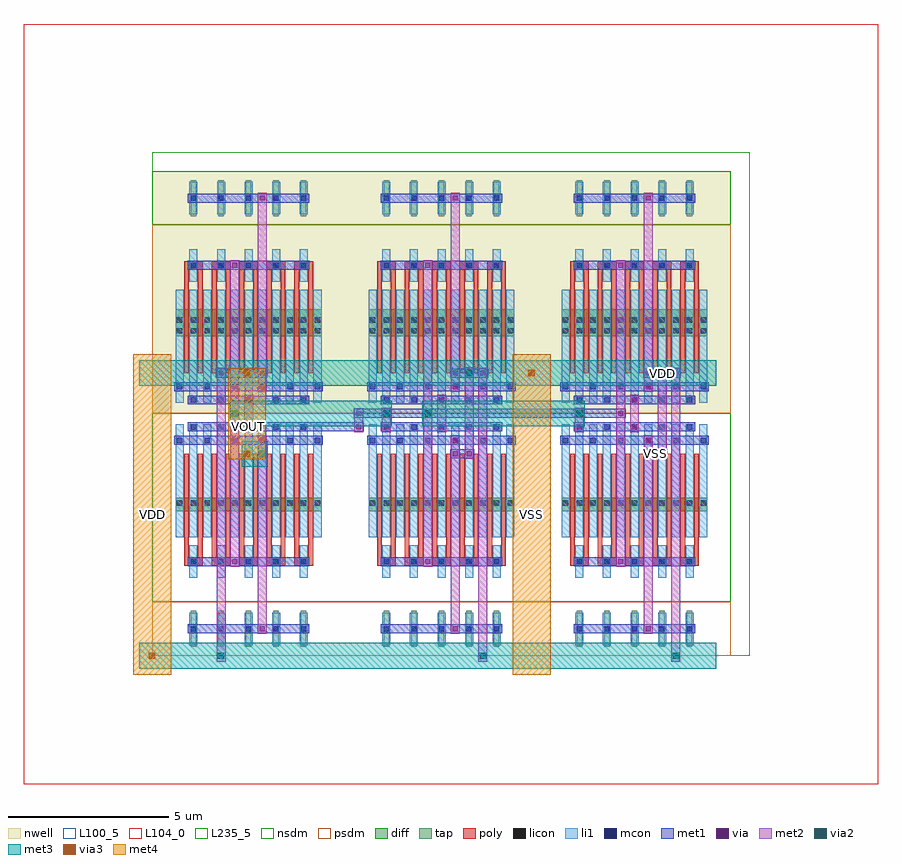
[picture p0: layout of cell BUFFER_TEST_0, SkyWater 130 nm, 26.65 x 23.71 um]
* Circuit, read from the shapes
.subckt BUFFER_TEST_0 VDD VOUT VSS
XM1 VOUT n1 VSS VSS sky130_fd_pr__nfet_01v8 w=0.42 l=0.15 m=10
XM2 n1 n2 VSS VSS sky130_fd_pr__nfet_01v8 w=0.42 l=0.15 m=10
XM3 n2 VOUT VSS VSS sky130_fd_pr__nfet_01v8 w=0.42 l=0.15 m=10
XM4 VOUT n1 VDD VDD sky130_fd_pr__pfet_01v8 w=0.84 l=0.15 m=10
XM5 n1 n2 VDD VDD sky130_fd_pr__pfet_01v8 w=0.84 l=0.15 m=10
XM6 n2 VOUT VDD VDD sky130_fd_pr__pfet_01v8 w=0.84 l=0.15 m=10
.ends

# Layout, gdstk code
import gdstk
lib = gdstk.Library(unit=1e-6, precision=1e-09)
def R(c, l, rs):  # rectangles x0, y0, x1, y1
    for r in rs: c.add(gdstk.rectangle(r[:2], r[2:], *l))
def A(c, l, x, y, w, h, nx, ny, dx, dy):  # array of equal rectangles
    R(c, l, [(x+i*dx, y+j*dy, x+i*dx+w, y+j*dy+h) for i in range(nx) for j in range(ny)])
def P(c, l, *ps):  # polygons
    for p in ps: c.add(gdstk.Polygon(p, *l))
nwell = (64, 20)
diff = (65, 20)
tap = (65, 44)
poly = (66, 20)
licon = (66, 44)
li1 = (67, 20)
mcon = (67, 44)
met1 = (68, 20)
via = (68, 44)
met2 = (69, 20)
via2 = (69, 44)
met3 = (70, 20)
via3 = (70, 44)
met4 = (71, 20)
nsdm = (93, 44)
psdm = (94, 20)
L100_5 = (100, 5)
L104_0 = (104, 0)
L235_5 = (235, 5)

nmos_s_94100000_x5_y1_16 = lib.new_cell('NMOS_S_94100000_X5_Y1_1677907802_1677907802_1677907802')
R(nmos_s_94100000_x5_y1_16, diff, [(0.735,2.625,5.285,3.045)])
A(nmos_s_94100000_x5_y1_16, tap, 1.205, 6.16, 0.17, 1.12, 5, 1, 0.86, 0)
A(nmos_s_94100000_x5_y1_16, poly, 1, 1.26, 0.15, 3.36, 10, 1, 0.43, 0)
A(nmos_s_94100000_x5_y1_16, poly, 1, 4.485, 0.58, 0.27, 5, 1, 0.86, 0)
A(nmos_s_94100000_x5_y1_16, licon, 0.775, 2.705, 0.17, 0.17, 3, 1, 0.43, 0)
A(nmos_s_94100000_x5_y1_16, licon, 1.635, 2.705, 0.17, 0.17, 3, 1, 0.43, 0)
A(nmos_s_94100000_x5_y1_16, licon, 2.495, 2.705, 0.17, 0.17, 3, 1, 0.43, 0)
A(nmos_s_94100000_x5_y1_16, licon, 3.355, 2.705, 0.17, 0.17, 3, 1, 0.43, 0)
A(nmos_s_94100000_x5_y1_16, licon, 4.215, 2.705, 0.17, 0.17, 3, 1, 0.43, 0)
A(nmos_s_94100000_x5_y1_16, licon, 1.205, 4.535, 0.17, 0.17, 5, 2, 0.86, 2.1)
A(nmos_s_94100000_x5_y1_16, li1, 0.735, 0.335, 0.25, 3.53, 11, 1, 0.43, 0)
A(nmos_s_94100000_x5_y1_16, li1, 1.165, 4.115, 0.25, 1.01, 5, 2, 0.86, 2.1)
A(nmos_s_94100000_x5_y1_16, mcon, 1.205, 0.335, 0.17, 0.17, 5, 2, 0.86, 4.2)
A(nmos_s_94100000_x5_y1_16, mcon, 0.775, 0.755, 0.17, 0.17, 6, 1, 0.86, 0)
A(nmos_s_94100000_x5_y1_16, mcon, 1.205, 6.635, 0.17, 0.17, 5, 1, 0.86, 0)
R(nmos_s_94100000_x5_y1_16, met1, [(1.12,0.28,4.9,0.56), (0.69,0.7,5.33,0.98), (1.12,4.48,4.9,4.76), (1.12,6.58,4.9,6.86)])
R(nmos_s_94100000_x5_y1_16, via, [(3.365,0.765,3.515,0.915), (3.365,6.645,3.515,6.795)])
R(nmos_s_94100000_x5_y1_16, met2, [(3.3,0.68,3.58,6.88)])
R(nmos_s_94100000_x5_y1_16, nsdm, [(0,0,6.02,5.88)])
R(nmos_s_94100000_x5_y1_16, psdm, [(0,5.88,6.02,7.56)])
R(nmos_s_94100000_x5_y1_16, L100_5, [(0,0,6.02,7.56)])

pmos_s_16969580_x5_y1_16 = lib.new_cell('PMOS_S_16969580_X5_Y1_1677907803_1677907802_1677907802')
R(pmos_s_16969580_x5_y1_16, nwell, [(0,0,6.02,7.56)])
R(pmos_s_16969580_x5_y1_16, diff, [(0.735,2.415,5.285,3.255)])
A(pmos_s_16969580_x5_y1_16, tap, 1.205, 6.16, 0.17, 1.12, 5, 1, 0.86, 0)
A(pmos_s_16969580_x5_y1_16, poly, 1, 1.26, 0.15, 3.36, 10, 1, 0.43, 0)
A(pmos_s_16969580_x5_y1_16, poly, 1, 4.485, 0.58, 0.27, 5, 1, 0.86, 0)
A(pmos_s_16969580_x5_y1_16, licon, 0.775, 2.495, 0.17, 0.17, 3, 2, 0.43, 0.34)
A(pmos_s_16969580_x5_y1_16, licon, 1.635, 2.495, 0.17, 0.17, 3, 2, 0.43, 0.34)
A(pmos_s_16969580_x5_y1_16, licon, 2.495, 2.495, 0.17, 0.17, 3, 2, 0.43, 0.34)
A(pmos_s_16969580_x5_y1_16, licon, 3.355, 2.495, 0.17, 0.17, 3, 2, 0.43, 0.34)
A(pmos_s_16969580_x5_y1_16, licon, 4.215, 2.495, 0.17, 0.17, 3, 2, 0.43, 0.34)
A(pmos_s_16969580_x5_y1_16, licon, 1.205, 4.535, 0.17, 0.17, 5, 2, 0.86, 2.1)
A(pmos_s_16969580_x5_y1_16, li1, 0.735, 0.335, 0.25, 3.53, 11, 1, 0.43, 0)
A(pmos_s_16969580_x5_y1_16, li1, 1.165, 4.115, 0.25, 1.01, 5, 2, 0.86, 2.1)
A(pmos_s_16969580_x5_y1_16, mcon, 1.205, 0.335, 0.17, 0.17, 5, 2, 0.86, 4.2)
A(pmos_s_16969580_x5_y1_16, mcon, 0.775, 0.755, 0.17, 0.17, 6, 1, 0.86, 0)
A(pmos_s_16969580_x5_y1_16, mcon, 1.205, 6.635, 0.17, 0.17, 5, 1, 0.86, 0)
R(pmos_s_16969580_x5_y1_16, met1, [(1.12,0.28,4.9,0.56), (0.69,0.7,5.33,0.98), (1.12,4.48,4.9,4.76), (1.12,6.58,4.9,6.86)])
R(pmos_s_16969580_x5_y1_16, via, [(3.365,0.765,3.515,0.915), (3.365,6.645,3.515,6.795)])
R(pmos_s_16969580_x5_y1_16, met2, [(3.3,0.68,3.58,6.88)])
R(pmos_s_16969580_x5_y1_16, nsdm, [(0,5.88,6.02,7.56)])
R(pmos_s_16969580_x5_y1_16, psdm, [(0,0,6.02,5.88)])
R(pmos_s_16969580_x5_y1_16, L100_5, [(0,0,6.02,7.56)])

inv_9852702_pg0_0_0_1677 = lib.new_cell('INV_9852702_PG0_0_0_1677907802_1677907802')
R(inv_9852702_pg0_0_0_1677, met1, [(2.42,2.8,2.74,3.08), (2.42,2.8,2.74,3.08), (2.85,7,3.17,7.28), (2.85,7,3.17,7.28), (2.85,7.84,3.17,8.12), (2.85,7.84,3.17,8.12), (2.42,12.04,2.74,12.32), (2.42,12.04,2.74,12.32)])
P(inv_9852702_pg0_0_0_1677, met1, [(0,0),(0,0),(0,0),(0,0)],
  [(0,0),(0,0),(0,0),(0,0)],
  [(0,0),(0,0),(0,0),(0,0)],
  [(0,0),(0,0),(0,0),(0,0)])
R(inv_9852702_pg0_0_0_1677, via, [(2.505,2.865,2.655,3.015), (2.505,2.865,2.655,3.015), (2.935,7.065,3.085,7.215), (2.935,7.065,3.085,7.215), (2.935,7.905,3.085,8.055), (2.935,7.905,3.085,8.055), (2.505,12.105,2.655,12.255), (2.505,12.105,2.655,12.255)])
R(inv_9852702_pg0_0_0_1677, met2, [(2.44,2.78,2.72,3.1), (2.44,2.78,2.72,3.1), (2.44,2.94,2.72,12.18), (2.87,6.98,3.15,7.3), (2.87,6.98,3.15,7.3), (2.87,7.14,3.15,7.98), (2.87,7.82,3.15,8.14), (2.87,7.82,3.15,8.14), (2.44,12.02,2.72,12.34), (2.44,12.02,2.72,12.34)])
P(inv_9852702_pg0_0_0_1677, met2, [(0,0),(0,0),(0,0),(0,0)],
  [(0,0),(0,0),(0,0),(0,0)])
R(inv_9852702_pg0_0_0_1677, L235_5, [(0,0,6.02,15.12)])
inv_9852702_pg0_0_0_1677.add(gdstk.Reference(nmos_s_94100000_x5_y1_16, (0,7.56), x_reflection=True))
inv_9852702_pg0_0_0_1677.add(gdstk.Reference(pmos_s_16969580_x5_y1_16, (0,7.56)))

buffer_test_stage_pg0_0_ = lib.new_cell('BUFFER_TEST_STAGE_PG0_0_0_1677907802')
P(buffer_test_stage_pg0_0_, met1, [(0,0),(0,0),(0,0),(0,0)],
  [(0,0),(0,0),(0,0),(0,0)],
  [(0,0),(0,0),(0,0),(0,0)],
  [(0,0),(0,0),(0,0),(0,0)],
  [(0,0),(0,0),(0,0),(0,0)],
  [(0,0),(0,0),(0,0),(0,0)],
  [(0,0),(0,0),(0,0),(0,0)],
  [(0,0),(0,0),(0,0),(0,0)])
P(buffer_test_stage_pg0_0_, met2, [(0,0),(0,0),(0,0),(0,0)],
  [(0,0),(0,0),(0,0),(0,0)])
R(buffer_test_stage_pg0_0_, L235_5, [(0,0,6.02,15.12)])
buffer_test_stage_pg0_0_.add(gdstk.Reference(inv_9852702_pg0_0_0_1677, (0,0)))

c_nmos_s_94100000_x5_y1_16 = lib.new_cell('NMOS_S_94100000_X5_Y1_1677907802_1677907802_1677907803')
R(c_nmos_s_94100000_x5_y1_16, diff, [(0.735,2.625,5.285,3.045)])
A(c_nmos_s_94100000_x5_y1_16, tap, 1.205, 6.16, 0.17, 1.12, 5, 1, 0.86, 0)
A(c_nmos_s_94100000_x5_y1_16, poly, 1, 1.26, 0.15, 3.36, 10, 1, 0.43, 0)
A(c_nmos_s_94100000_x5_y1_16, poly, 1, 4.485, 0.58, 0.27, 5, 1, 0.86, 0)
A(c_nmos_s_94100000_x5_y1_16, licon, 0.775, 2.705, 0.17, 0.17, 3, 1, 0.43, 0)
A(c_nmos_s_94100000_x5_y1_16, licon, 1.635, 2.705, 0.17, 0.17, 3, 1, 0.43, 0)
A(c_nmos_s_94100000_x5_y1_16, licon, 2.495, 2.705, 0.17, 0.17, 3, 1, 0.43, 0)
A(c_nmos_s_94100000_x5_y1_16, licon, 3.355, 2.705, 0.17, 0.17, 3, 1, 0.43, 0)
A(c_nmos_s_94100000_x5_y1_16, licon, 4.215, 2.705, 0.17, 0.17, 3, 1, 0.43, 0)
A(c_nmos_s_94100000_x5_y1_16, licon, 1.205, 4.535, 0.17, 0.17, 5, 2, 0.86, 2.1)
A(c_nmos_s_94100000_x5_y1_16, li1, 0.735, 0.335, 0.25, 3.53, 11, 1, 0.43, 0)
A(c_nmos_s_94100000_x5_y1_16, li1, 1.165, 4.115, 0.25, 1.01, 5, 2, 0.86, 2.1)
A(c_nmos_s_94100000_x5_y1_16, mcon, 1.205, 0.335, 0.17, 0.17, 5, 2, 0.86, 4.2)
A(c_nmos_s_94100000_x5_y1_16, mcon, 0.775, 0.755, 0.17, 0.17, 6, 1, 0.86, 0)
A(c_nmos_s_94100000_x5_y1_16, mcon, 1.205, 6.635, 0.17, 0.17, 5, 1, 0.86, 0)
R(c_nmos_s_94100000_x5_y1_16, met1, [(1.12,0.28,4.9,0.56), (0.69,0.7,5.33,0.98), (1.12,4.48,4.9,4.76), (1.12,6.58,4.9,6.86)])
R(c_nmos_s_94100000_x5_y1_16, via, [(3.365,0.765,3.515,0.915), (3.365,6.645,3.515,6.795)])
R(c_nmos_s_94100000_x5_y1_16, met2, [(3.3,0.68,3.58,6.88)])
R(c_nmos_s_94100000_x5_y1_16, nsdm, [(0,0,6.02,5.88)])
R(c_nmos_s_94100000_x5_y1_16, psdm, [(0,5.88,6.02,7.56)])
R(c_nmos_s_94100000_x5_y1_16, L100_5, [(0,0,6.02,7.56)])

c_pmos_s_16969580_x5_y1_16 = lib.new_cell('PMOS_S_16969580_X5_Y1_1677907803_1677907802_1677907803')
R(c_pmos_s_16969580_x5_y1_16, nwell, [(0,0,6.02,7.56)])
R(c_pmos_s_16969580_x5_y1_16, diff, [(0.735,2.415,5.285,3.255)])
A(c_pmos_s_16969580_x5_y1_16, tap, 1.205, 6.16, 0.17, 1.12, 5, 1, 0.86, 0)
A(c_pmos_s_16969580_x5_y1_16, poly, 1, 1.26, 0.15, 3.36, 10, 1, 0.43, 0)
A(c_pmos_s_16969580_x5_y1_16, poly, 1, 4.485, 0.58, 0.27, 5, 1, 0.86, 0)
A(c_pmos_s_16969580_x5_y1_16, licon, 0.775, 2.495, 0.17, 0.17, 3, 2, 0.43, 0.34)
A(c_pmos_s_16969580_x5_y1_16, licon, 1.635, 2.495, 0.17, 0.17, 3, 2, 0.43, 0.34)
A(c_pmos_s_16969580_x5_y1_16, licon, 2.495, 2.495, 0.17, 0.17, 3, 2, 0.43, 0.34)
A(c_pmos_s_16969580_x5_y1_16, licon, 3.355, 2.495, 0.17, 0.17, 3, 2, 0.43, 0.34)
A(c_pmos_s_16969580_x5_y1_16, licon, 4.215, 2.495, 0.17, 0.17, 3, 2, 0.43, 0.34)
A(c_pmos_s_16969580_x5_y1_16, licon, 1.205, 4.535, 0.17, 0.17, 5, 2, 0.86, 2.1)
A(c_pmos_s_16969580_x5_y1_16, li1, 0.735, 0.335, 0.25, 3.53, 11, 1, 0.43, 0)
A(c_pmos_s_16969580_x5_y1_16, li1, 1.165, 4.115, 0.25, 1.01, 5, 2, 0.86, 2.1)
A(c_pmos_s_16969580_x5_y1_16, mcon, 1.205, 0.335, 0.17, 0.17, 5, 2, 0.86, 4.2)
A(c_pmos_s_16969580_x5_y1_16, mcon, 0.775, 0.755, 0.17, 0.17, 6, 1, 0.86, 0)
A(c_pmos_s_16969580_x5_y1_16, mcon, 1.205, 6.635, 0.17, 0.17, 5, 1, 0.86, 0)
R(c_pmos_s_16969580_x5_y1_16, met1, [(1.12,0.28,4.9,0.56), (0.69,0.7,5.33,0.98), (1.12,4.48,4.9,4.76), (1.12,6.58,4.9,6.86)])
R(c_pmos_s_16969580_x5_y1_16, via, [(3.365,0.765,3.515,0.915), (3.365,6.645,3.515,6.795)])
R(c_pmos_s_16969580_x5_y1_16, met2, [(3.3,0.68,3.58,6.88)])
R(c_pmos_s_16969580_x5_y1_16, nsdm, [(0,5.88,6.02,7.56)])
R(c_pmos_s_16969580_x5_y1_16, psdm, [(0,0,6.02,5.88)])
R(c_pmos_s_16969580_x5_y1_16, L100_5, [(0,0,6.02,7.56)])

inv_9852702_pg0_1_0_1677 = lib.new_cell('INV_9852702_PG0_1_0_1677907802_1677907803')
R(inv_9852702_pg0_1_0_1677, met1, [(2.42,2.8,2.74,3.08), (2.42,2.8,2.74,3.08), (2.85,7,3.17,7.28), (2.85,7,3.17,7.28), (2.85,7.84,3.17,8.12), (2.85,7.84,3.17,8.12), (2.42,12.04,2.74,12.32), (2.42,12.04,2.74,12.32)])
P(inv_9852702_pg0_1_0_1677, met1, [(0,0),(0,0),(0,0),(0,0)],
  [(0,0),(0,0),(0,0),(0,0)],
  [(0,0),(0,0),(0,0),(0,0)],
  [(0,0),(0,0),(0,0),(0,0)])
R(inv_9852702_pg0_1_0_1677, via, [(2.505,2.865,2.655,3.015), (2.505,2.865,2.655,3.015), (2.935,7.065,3.085,7.215), (2.935,7.065,3.085,7.215), (2.935,7.905,3.085,8.055), (2.935,7.905,3.085,8.055), (2.505,12.105,2.655,12.255), (2.505,12.105,2.655,12.255)])
R(inv_9852702_pg0_1_0_1677, met2, [(2.44,2.78,2.72,3.1), (2.44,2.78,2.72,3.1), (2.44,2.94,2.72,12.18), (2.87,6.98,3.15,7.3), (2.87,6.98,3.15,7.3), (2.87,7.14,3.15,7.98), (2.87,7.82,3.15,8.14), (2.87,7.82,3.15,8.14), (2.44,12.02,2.72,12.34), (2.44,12.02,2.72,12.34)])
P(inv_9852702_pg0_1_0_1677, met2, [(0,0),(0,0),(0,0),(0,0)],
  [(0,0),(0,0),(0,0),(0,0)])
R(inv_9852702_pg0_1_0_1677, L235_5, [(0,0,6.02,15.12)])
inv_9852702_pg0_1_0_1677.add(gdstk.Reference(c_nmos_s_94100000_x5_y1_16, (0,7.56), x_reflection=True))
inv_9852702_pg0_1_0_1677.add(gdstk.Reference(c_pmos_s_16969580_x5_y1_16, (0,7.56)))

buffer_test_stage_pg0_1_ = lib.new_cell('BUFFER_TEST_STAGE_PG0_1_0_1677907803')
P(buffer_test_stage_pg0_1_, met1, [(0,0),(0,0),(0,0),(0,0)],
  [(0,0),(0,0),(0,0),(0,0)],
  [(0,0),(0,0),(0,0),(0,0)],
  [(0,0),(0,0),(0,0),(0,0)],
  [(0,0),(0,0),(0,0),(0,0)],
  [(0,0),(0,0),(0,0),(0,0)],
  [(0,0),(0,0),(0,0),(0,0)],
  [(0,0),(0,0),(0,0),(0,0)])
P(buffer_test_stage_pg0_1_, met2, [(0,0),(0,0),(0,0),(0,0)],
  [(0,0),(0,0),(0,0),(0,0)])
R(buffer_test_stage_pg0_1_, L235_5, [(0,0,6.02,15.12)])
buffer_test_stage_pg0_1_.add(gdstk.Reference(inv_9852702_pg0_1_0_1677, (0,0)))

c_nmos_s_94100000_x5_y1_16_ = lib.new_cell('NMOS_S_94100000_X5_Y1_1677907802_1677907802_1677907804')
R(c_nmos_s_94100000_x5_y1_16_, diff, [(0.735,2.625,5.285,3.045)])
A(c_nmos_s_94100000_x5_y1_16_, tap, 1.205, 6.16, 0.17, 1.12, 5, 1, 0.86, 0)
A(c_nmos_s_94100000_x5_y1_16_, poly, 1, 1.26, 0.15, 3.36, 10, 1, 0.43, 0)
A(c_nmos_s_94100000_x5_y1_16_, poly, 1, 4.485, 0.58, 0.27, 5, 1, 0.86, 0)
A(c_nmos_s_94100000_x5_y1_16_, licon, 0.775, 2.705, 0.17, 0.17, 3, 1, 0.43, 0)
A(c_nmos_s_94100000_x5_y1_16_, licon, 1.635, 2.705, 0.17, 0.17, 3, 1, 0.43, 0)
A(c_nmos_s_94100000_x5_y1_16_, licon, 2.495, 2.705, 0.17, 0.17, 3, 1, 0.43, 0)
A(c_nmos_s_94100000_x5_y1_16_, licon, 3.355, 2.705, 0.17, 0.17, 3, 1, 0.43, 0)
A(c_nmos_s_94100000_x5_y1_16_, licon, 4.215, 2.705, 0.17, 0.17, 3, 1, 0.43, 0)
A(c_nmos_s_94100000_x5_y1_16_, licon, 1.205, 4.535, 0.17, 0.17, 5, 2, 0.86, 2.1)
A(c_nmos_s_94100000_x5_y1_16_, li1, 0.735, 0.335, 0.25, 3.53, 11, 1, 0.43, 0)
A(c_nmos_s_94100000_x5_y1_16_, li1, 1.165, 4.115, 0.25, 1.01, 5, 2, 0.86, 2.1)
A(c_nmos_s_94100000_x5_y1_16_, mcon, 1.205, 0.335, 0.17, 0.17, 5, 2, 0.86, 4.2)
A(c_nmos_s_94100000_x5_y1_16_, mcon, 0.775, 0.755, 0.17, 0.17, 6, 1, 0.86, 0)
A(c_nmos_s_94100000_x5_y1_16_, mcon, 1.205, 6.635, 0.17, 0.17, 5, 1, 0.86, 0)
R(c_nmos_s_94100000_x5_y1_16_, met1, [(1.12,0.28,4.9,0.56), (0.69,0.7,5.33,0.98), (1.12,4.48,4.9,4.76), (1.12,6.58,4.9,6.86)])
R(c_nmos_s_94100000_x5_y1_16_, via, [(3.365,0.765,3.515,0.915), (3.365,6.645,3.515,6.795)])
R(c_nmos_s_94100000_x5_y1_16_, met2, [(3.3,0.68,3.58,6.88)])
R(c_nmos_s_94100000_x5_y1_16_, nsdm, [(0,0,6.02,5.88)])
R(c_nmos_s_94100000_x5_y1_16_, psdm, [(0,5.88,6.02,7.56)])
R(c_nmos_s_94100000_x5_y1_16_, L100_5, [(0,0,6.02,7.56)])

c_pmos_s_16969580_x5_y1_16_ = lib.new_cell('PMOS_S_16969580_X5_Y1_1677907803_1677907802_1677907804')
R(c_pmos_s_16969580_x5_y1_16_, nwell, [(0,0,6.02,7.56)])
R(c_pmos_s_16969580_x5_y1_16_, diff, [(0.735,2.415,5.285,3.255)])
A(c_pmos_s_16969580_x5_y1_16_, tap, 1.205, 6.16, 0.17, 1.12, 5, 1, 0.86, 0)
A(c_pmos_s_16969580_x5_y1_16_, poly, 1, 1.26, 0.15, 3.36, 10, 1, 0.43, 0)
A(c_pmos_s_16969580_x5_y1_16_, poly, 1, 4.485, 0.58, 0.27, 5, 1, 0.86, 0)
A(c_pmos_s_16969580_x5_y1_16_, licon, 0.775, 2.495, 0.17, 0.17, 3, 2, 0.43, 0.34)
A(c_pmos_s_16969580_x5_y1_16_, licon, 1.635, 2.495, 0.17, 0.17, 3, 2, 0.43, 0.34)
A(c_pmos_s_16969580_x5_y1_16_, licon, 2.495, 2.495, 0.17, 0.17, 3, 2, 0.43, 0.34)
A(c_pmos_s_16969580_x5_y1_16_, licon, 3.355, 2.495, 0.17, 0.17, 3, 2, 0.43, 0.34)
A(c_pmos_s_16969580_x5_y1_16_, licon, 4.215, 2.495, 0.17, 0.17, 3, 2, 0.43, 0.34)
A(c_pmos_s_16969580_x5_y1_16_, licon, 1.205, 4.535, 0.17, 0.17, 5, 2, 0.86, 2.1)
A(c_pmos_s_16969580_x5_y1_16_, li1, 0.735, 0.335, 0.25, 3.53, 11, 1, 0.43, 0)
A(c_pmos_s_16969580_x5_y1_16_, li1, 1.165, 4.115, 0.25, 1.01, 5, 2, 0.86, 2.1)
A(c_pmos_s_16969580_x5_y1_16_, mcon, 1.205, 0.335, 0.17, 0.17, 5, 2, 0.86, 4.2)
A(c_pmos_s_16969580_x5_y1_16_, mcon, 0.775, 0.755, 0.17, 0.17, 6, 1, 0.86, 0)
A(c_pmos_s_16969580_x5_y1_16_, mcon, 1.205, 6.635, 0.17, 0.17, 5, 1, 0.86, 0)
R(c_pmos_s_16969580_x5_y1_16_, met1, [(1.12,0.28,4.9,0.56), (0.69,0.7,5.33,0.98), (1.12,4.48,4.9,4.76), (1.12,6.58,4.9,6.86)])
R(c_pmos_s_16969580_x5_y1_16_, via, [(3.365,0.765,3.515,0.915), (3.365,6.645,3.515,6.795)])
R(c_pmos_s_16969580_x5_y1_16_, met2, [(3.3,0.68,3.58,6.88)])
R(c_pmos_s_16969580_x5_y1_16_, nsdm, [(0,5.88,6.02,7.56)])
R(c_pmos_s_16969580_x5_y1_16_, psdm, [(0,0,6.02,5.88)])
R(c_pmos_s_16969580_x5_y1_16_, L100_5, [(0,0,6.02,7.56)])

inv_9852702_pg0_2_0_1677 = lib.new_cell('INV_9852702_PG0_2_0_1677907802_1677907804')
R(inv_9852702_pg0_2_0_1677, met1, [(2.42,2.8,2.74,3.08), (2.42,2.8,2.74,3.08), (2.85,7,3.17,7.28), (2.85,7,3.17,7.28), (2.85,7.84,3.17,8.12), (2.85,7.84,3.17,8.12), (2.42,12.04,2.74,12.32), (2.42,12.04,2.74,12.32)])
P(inv_9852702_pg0_2_0_1677, met1, [(0,0),(0,0),(0,0),(0,0)],
  [(0,0),(0,0),(0,0),(0,0)],
  [(0,0),(0,0),(0,0),(0,0)],
  [(0,0),(0,0),(0,0),(0,0)])
R(inv_9852702_pg0_2_0_1677, via, [(2.505,2.865,2.655,3.015), (2.505,2.865,2.655,3.015), (2.935,7.065,3.085,7.215), (2.935,7.065,3.085,7.215), (2.935,7.905,3.085,8.055), (2.935,7.905,3.085,8.055), (2.505,12.105,2.655,12.255), (2.505,12.105,2.655,12.255)])
R(inv_9852702_pg0_2_0_1677, met2, [(2.44,2.78,2.72,3.1), (2.44,2.78,2.72,3.1), (2.44,2.94,2.72,12.18), (2.87,6.98,3.15,7.3), (2.87,6.98,3.15,7.3), (2.87,7.14,3.15,7.98), (2.87,7.82,3.15,8.14), (2.87,7.82,3.15,8.14), (2.44,12.02,2.72,12.34), (2.44,12.02,2.72,12.34)])
P(inv_9852702_pg0_2_0_1677, met2, [(0,0),(0,0),(0,0),(0,0)],
  [(0,0),(0,0),(0,0),(0,0)])
R(inv_9852702_pg0_2_0_1677, L235_5, [(0,0,6.02,15.12)])
inv_9852702_pg0_2_0_1677.add(gdstk.Reference(c_nmos_s_94100000_x5_y1_16_, (0,7.56), x_reflection=True))
inv_9852702_pg0_2_0_1677.add(gdstk.Reference(c_pmos_s_16969580_x5_y1_16_, (0,7.56)))

buffer_test_stage_pg0_2_ = lib.new_cell('BUFFER_TEST_STAGE_PG0_2_0_1677907804')
P(buffer_test_stage_pg0_2_, met1, [(0,0),(0,0),(0,0),(0,0)],
  [(0,0),(0,0),(0,0),(0,0)],
  [(0,0),(0,0),(0,0),(0,0)],
  [(0,0),(0,0),(0,0),(0,0)],
  [(0,0),(0,0),(0,0),(0,0)],
  [(0,0),(0,0),(0,0),(0,0)],
  [(0,0),(0,0),(0,0),(0,0)],
  [(0,0),(0,0),(0,0),(0,0)])
P(buffer_test_stage_pg0_2_, met2, [(0,0),(0,0),(0,0),(0,0)],
  [(0,0),(0,0),(0,0),(0,0)])
R(buffer_test_stage_pg0_2_, L235_5, [(0,0,6.02,15.12)])
buffer_test_stage_pg0_2_.add(gdstk.Reference(inv_9852702_pg0_2_0_1677, (0,0)))

buffer_test_0 = lib.new_cell('BUFFER_TEST_0')
R(buffer_test_0, met1, [(9.3,6.16,9.62,6.44), (9.3,6.16,9.62,6.44), (9.3,6.16,9.62,6.44), (9.46,6.16,9.89,6.44), (9.73,6.16,10.05,6.44), (9.73,6.16,10.05,6.44), (9.73,6.16,10.05,6.44), (15.32,6.16,15.64,6.44), (15.32,6.16,15.64,6.44), (15.32,6.16,15.64,6.44), (15.32,6.16,15.64,6.44), (15.48,6.16,15.91,6.44), (15.75,6.16,16.07,6.44), (15.75,6.16,16.07,6.44), (15.75,6.16,16.07,6.44), (15.75,6.16,16.07,6.44), (4.73,7,6.45,7.28), (6.29,7,6.61,7.28), (6.29,7,6.61,7.28), (7.15,7,7.47,7.28), (7.15,7,7.47,7.28), (13.17,7,13.49,7.28), (13.17,7,13.49,7.28), (6.29,7.42,6.61,7.7), (6.29,7.42,6.61,7.7), (6.45,7.42,14.62,7.7), (14.46,7.42,14.78,7.7), (14.46,7.42,14.78,7.7), (1.99,8.68,2.31,8.96), (1.99,8.68,2.31,8.96), (2.15,8.68,3.44,8.96), (3.28,8.68,3.6,8.96), (3.28,8.68,3.6,8.96), (9.3,8.68,9.62,8.96), (9.3,8.68,9.62,8.96), (9.3,8.68,9.62,8.96), (9.46,8.68,10.32,8.96), (10.16,8.68,10.48,8.96), (10.16,8.68,10.48,8.96), (10.16,8.68,10.48,8.96), (15.32,8.68,15.64,8.96), (15.32,8.68,15.64,8.96), (15.32,8.68,15.64,8.96), (15.32,8.68,15.64,8.96), (15.48,8.68,16.34,8.96), (16.18,8.68,16.5,8.96), (16.18,8.68,16.5,8.96), (16.18,8.68,16.5,8.96), (16.18,8.68,16.5,8.96)])
P(buffer_test_0, met1, [(0,0),(0,0),(0,0),(0,0)],
  [(0,0),(0,0),(0,0),(0,0)],
  [(0,0),(0,0),(0,0),(0,0)],
  [(0,0),(0,0),(0,0),(0,0)],
  [(0,0),(0,0),(0,0),(0,0)],
  [(0,0),(0,0),(0,0),(0,0)],
  [(0,0),(0,0),(0,0),(0,0)],
  [(0,0),(0,0),(0,0),(0,0)],
  [(0,0),(0,0),(0,0),(0,0)],
  [(0,0),(0,0),(0,0),(0,0)],
  [(0,0),(0,0),(0,0),(0,0)],
  [(0,0),(0,0),(0,0),(0,0)],
  [(0,0),(0,0),(0,0),(0,0)],
  [(0,0),(0,0),(0,0),(0,0)],
  [(0,0),(0,0),(0,0),(0,0)],
  [(0,0),(0,0),(0,0),(0,0)],
  [(0,0),(0,0),(0,0),(0,0)],
  [(0,0),(0,0),(0,0),(0,0)],
  [(0,0),(0,0),(0,0),(0,0)],
  [(0,0),(0,0),(0,0),(0,0)],
  [(0,0),(0,0),(0,0),(0,0)],
  [(0,0),(0,0),(0,0),(0,0)],
  [(0,0),(0,0),(0,0),(0,0)],
  [(0,0),(0,0),(0,0),(0,0)],
  [(0,0),(0,0),(0,0),(0,0)])
R(buffer_test_0, via, [(9.385,6.225,9.535,6.375), (9.385,6.225,9.535,6.375), (9.385,6.225,9.535,6.375), (9.815,6.225,9.965,6.375), (9.815,6.225,9.965,6.375), (9.815,6.225,9.965,6.375), (15.405,6.225,15.555,6.375), (15.405,6.225,15.555,6.375), (15.405,6.225,15.555,6.375), (15.405,6.225,15.555,6.375), (15.835,6.225,15.985,6.375), (15.835,6.225,15.985,6.375), (15.835,6.225,15.985,6.375), (15.835,6.225,15.985,6.375), (6.375,7.065,6.525,7.215), (6.375,7.065,6.525,7.215), (7.235,7.065,7.385,7.215), (7.235,7.065,7.385,7.215), (13.255,7.065,13.405,7.215), (13.255,7.065,13.405,7.215), (6.375,7.485,6.525,7.635), (6.375,7.485,6.525,7.635), (14.545,7.485,14.695,7.635), (14.545,7.485,14.695,7.635), (2.075,8.745,2.225,8.895), (2.075,8.745,2.225,8.895), (3.365,8.745,3.515,8.895), (3.365,8.745,3.515,8.895), (9.385,8.745,9.535,8.895), (9.385,8.745,9.535,8.895), (9.385,8.745,9.535,8.895), (10.245,8.745,10.395,8.895), (10.245,8.745,10.395,8.895), (10.245,8.745,10.395,8.895), (15.405,8.745,15.555,8.895), (15.405,8.745,15.555,8.895), (15.405,8.745,15.555,8.895), (15.405,8.745,15.555,8.895), (16.265,8.745,16.415,8.895), (16.265,8.745,16.415,8.895), (16.265,8.745,16.415,8.895), (16.265,8.745,16.415,8.895)])
R(buffer_test_0, met2, [(2.01,-0.185,2.29,0.185), (2.01,-0.185,2.29,0.185), (10.18,-0.185,10.46,0.185), (10.18,-0.185,10.46,0.185), (10.18,-0.185,10.46,0.185), (16.2,-0.185,16.48,0.185), (16.2,-0.185,16.48,0.185), (16.2,-0.185,16.48,0.185), (16.2,-0.185,16.48,0.185), (2.01,0,2.29,8.82), (10.18,0,10.46,8.82), (16.2,0,16.48,8.82), (3.3,6.115,3.58,6.485), (3.3,6.115,3.58,6.485), (9.32,6.14,9.6,6.46), (9.32,6.14,9.6,6.46), (9.32,6.14,9.6,6.46), (9.75,6.14,10.03,6.46), (9.75,6.14,10.03,6.46), (9.75,6.14,10.03,6.46), (15.34,6.14,15.62,6.46), (15.34,6.14,15.62,6.46), (15.34,6.14,15.62,6.46), (15.34,6.14,15.62,6.46), (15.77,6.14,16.05,6.46), (15.77,6.14,16.05,6.46), (15.77,6.14,16.05,6.46), (15.77,6.14,16.05,6.46), (9.75,6.3,10.03,8.82), (15.77,6.3,16.05,8.82), (6.31,6.98,6.59,7.3), (6.31,6.98,6.59,7.3), (7.17,6.98,7.45,7.3), (7.17,6.98,7.45,7.3), (13.19,6.98,13.47,7.3), (13.19,6.98,13.47,7.3), (6.31,7.14,6.59,7.56), (7.17,7.14,7.45,7.56), (13.19,7.14,13.47,7.56), (2.44,7.375,2.72,7.745), (2.44,7.375,2.72,7.745), (7.17,7.375,7.45,7.745), (7.17,7.375,7.45,7.745), (8.46,7.375,8.74,7.745), (8.46,7.375,8.74,7.745), (13.19,7.375,13.47,7.745), (13.19,7.375,13.47,7.745), (6.31,7.4,6.59,7.72), (6.31,7.4,6.59,7.72), (14.48,7.4,14.76,7.72), (14.48,7.4,14.76,7.72), (9.75,8.635,10.03,9.005), (9.75,8.635,10.03,9.005), (9.75,8.635,10.03,9.005), (15.77,8.635,16.05,9.005), (15.77,8.635,16.05,9.005), (15.77,8.635,16.05,9.005), (15.77,8.635,16.05,9.005), (2.01,8.66,2.29,8.98), (2.01,8.66,2.29,8.98), (3.3,8.66,3.58,8.98), (3.3,8.66,3.58,8.98), (9.32,8.66,9.6,8.98), (9.32,8.66,9.6,8.98), (9.32,8.66,9.6,8.98), (10.18,8.66,10.46,8.98), (10.18,8.66,10.46,8.98), (10.18,8.66,10.46,8.98), (15.34,8.66,15.62,8.98), (15.34,8.66,15.62,8.98), (15.34,8.66,15.62,8.98), (15.34,8.66,15.62,8.98), (16.2,8.66,16.48,8.98), (16.2,8.66,16.48,8.98), (16.2,8.66,16.48,8.98), (16.2,8.66,16.48,8.98)])
P(buffer_test_0, met2, [(0,0),(0,0),(0,0),(0,0)],
  [(0,0),(0,0),(0,0),(0,0)],
  [(0,0),(0,0),(0,0),(0,0)],
  [(0,0),(0,0),(0,0),(0,0)],
  [(0,0),(0,0),(0,0),(0,0)],
  [(0,0),(0,0),(0,0),(0,0)])
R(buffer_test_0, via2, [(2.05,-0.1,2.25,0.1), (2.05,-0.1,2.25,0.1), (10.22,-0.1,10.42,0.1), (10.22,-0.1,10.42,0.1), (10.22,-0.1,10.42,0.1), (16.24,-0.1,16.44,0.1), (16.24,-0.1,16.44,0.1), (16.24,-0.1,16.44,0.1), (16.24,-0.1,16.44,0.1), (3.34,6.2,3.54,6.4), (3.34,6.2,3.54,6.4), (2.48,7.46,2.68,7.66), (2.48,7.46,2.68,7.66), (7.21,7.46,7.41,7.66), (7.21,7.46,7.41,7.66), (8.5,7.46,8.7,7.66), (8.5,7.46,8.7,7.66), (13.23,7.46,13.43,7.66), (13.23,7.46,13.43,7.66), (9.79,8.72,9.99,8.92), (9.79,8.72,9.99,8.92), (9.79,8.72,9.99,8.92), (15.81,8.72,16.01,8.92), (15.81,8.72,16.01,8.92), (15.81,8.72,16.01,8.92), (15.81,8.72,16.01,8.92)])
A(buffer_test_0, met3, -0.4, -0.4, 4.24, 0.8, 3, 2, 3.44, 8.82)
R(buffer_test_0, met3, [(-0.165,-0.4,0.165,0.4), (1.985,-0.4,2.315,0.4), (1.985,-0.4,2.315,0.4), (9.92,-0.4,12.24,0.4), (10.155,-0.4,10.485,0.4), (10.155,-0.4,10.485,0.4), (10.155,-0.4,10.485,0.4), (11.44,-0.4,14.16,0.4), (13.36,-0.4,17.6,0.4), (16.175,-0.4,16.505,0.4), (16.175,-0.4,16.505,0.4), (16.175,-0.4,16.505,0.4), (16.175,-0.4,16.505,0.4), (2.795,5.9,3.125,6.7), (2.795,5.9,3.125,6.7), (2.96,5.9,3.44,6.7), (3.275,5.9,3.605,6.7), (3.275,5.9,3.605,6.7), (2.415,7.16,2.745,7.96), (2.415,7.16,2.745,7.96), (2.58,7.16,7.31,7.96), (7.145,7.16,7.475,7.96), (7.145,7.16,7.475,7.96), (8.435,7.16,8.765,7.96), (8.435,7.16,8.765,7.96), (8.6,7.16,13.33,7.96), (13.165,7.16,13.495,7.96), (13.165,7.16,13.495,7.96), (2.795,8.42,3.125,9.22), (2.795,8.42,3.125,9.22), (9.725,8.42,10.055,9.22), (9.725,8.42,10.055,9.22), (9.725,8.42,10.055,9.22), (9.92,8.42,12.24,9.22), (11.44,8.42,14.16,9.22), (11.675,8.42,12.005,9.22), (13.36,8.42,17.6,9.22), (15.745,8.42,16.075,9.22), (15.745,8.42,16.075,9.22), (15.745,8.42,16.075,9.22), (15.745,8.42,16.075,9.22)])
R(buffer_test_0, via3, [(-0.1,-0.1,0.1,0.1), (2.86,6.2,3.06,6.4), (2.86,6.2,3.06,6.4), (2.86,8.72,3.06,8.92), (2.86,8.72,3.06,8.92), (11.74,8.72,11.94,8.92)])
R(buffer_test_0, met4, [(-0.59,-0.59,0.59,9.41), (11.25,-0.59,12.43,9.41), (-0.59,-0.165,0.59,0.165), (2.37,6.135,3.55,6.465), (2.37,6.135,3.55,6.465), (2.37,6.3,3.55,8.82), (2.37,8.655,3.55,8.985), (2.37,8.655,3.55,8.985), (11.25,8.655,12.43,8.985)])
R(buffer_test_0, L104_0, [(-4,-4,22.65,19.71)])
R(buffer_test_0, L235_5, [(0,0,18.65,15.71)])
buffer_test_0.add(gdstk.Reference(buffer_test_stage_pg0_0_, (12.04,0)))
buffer_test_0.add(gdstk.Reference(buffer_test_stage_pg0_1_, (6.02,0)))
buffer_test_0.add(gdstk.Reference(buffer_test_stage_pg0_2_, (0,0)))
buffer_test_0.add(gdstk.Label('VOUT', (3.01,7.14), layer=68, texttype=5))
buffer_test_0.add(gdstk.Label('VSS', (11.84,4.41), layer=71, texttype=5))
buffer_test_0.add(gdstk.Label('VSS', (15.695,6.3), layer=68, texttype=5))
buffer_test_0.add(gdstk.Label('VSS', (11.84,4.41), layer=71, texttype=5))
buffer_test_0.add(gdstk.Label('VSS', (11.84,4.41), layer=71, texttype=5))
buffer_test_0.add(gdstk.Label('VSS', (11.84,4.41), layer=71, texttype=5))
buffer_test_0.add(gdstk.Label('VSS', (11.84,4.41), layer=71, texttype=5))
buffer_test_0.add(gdstk.Label('VSS', (11.84,4.41), layer=71, texttype=5))
buffer_test_0.add(gdstk.Label('VSS', (11.84,4.41), layer=71, texttype=5))
buffer_test_0.add(gdstk.Label('VSS', (11.84,4.41), layer=71, texttype=5))
buffer_test_0.add(gdstk.Label('VSS', (11.84,4.41), layer=71, texttype=5))
buffer_test_0.add(gdstk.Label('VSS', (11.84,4.41), layer=71, texttype=5))
buffer_test_0.add(gdstk.Label('VSS', (11.84,4.41), layer=71, texttype=5))
buffer_test_0.add(gdstk.Label('VSS', (11.84,4.41), layer=71, texttype=5))
buffer_test_0.add(gdstk.Label('VDD', (0,4.41), layer=71, texttype=5))
buffer_test_0.add(gdstk.Label('VDD', (15.91,8.82), layer=68, texttype=5))
buffer_test_0.add(gdstk.Label('VDD', (0,4.41), layer=71, texttype=5))
buffer_test_0.add(gdstk.Label('VDD', (0,4.41), layer=71, texttype=5))
buffer_test_0.add(gdstk.Label('VDD', (0,4.41), layer=71, texttype=5))
buffer_test_0.add(gdstk.Label('VDD', (0,4.41), layer=71, texttype=5))
buffer_test_0.add(gdstk.Label('VDD', (0,4.41), layer=71, texttype=5))
buffer_test_0.add(gdstk.Label('VDD', (0,4.41), layer=71, texttype=5))
buffer_test_0.add(gdstk.Label('VDD', (0,4.41), layer=71, texttype=5))
buffer_test_0.add(gdstk.Label('VDD', (0,4.41), layer=71, texttype=5))
buffer_test_0.add(gdstk.Label('VDD', (0,4.41), layer=71, texttype=5))
buffer_test_0.add(gdstk.Label('VDD', (0,4.41), layer=71, texttype=5))
buffer_test_0.add(gdstk.Label('VDD', (0,4.41), layer=71, texttype=5))

lib.write_gds('BUFFER_TEST_0.gds')
